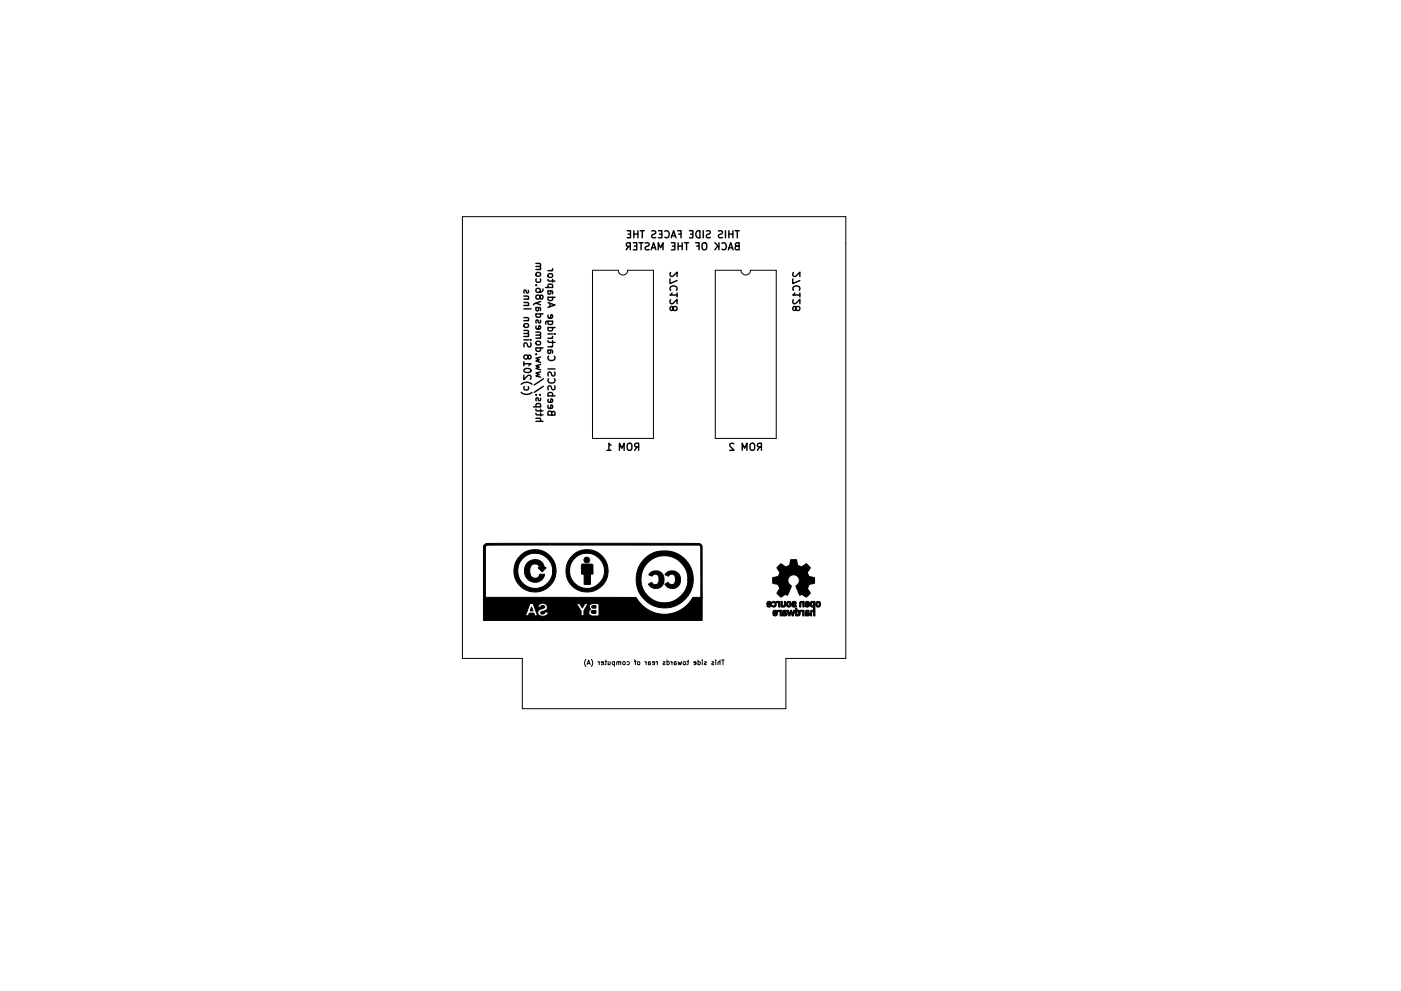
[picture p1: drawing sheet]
<svg xmlns="http://www.w3.org/2000/svg" width="297mm" height="210mm" viewBox="0 0 297 210" stroke-linecap="round" stroke-linejoin="round" font-family="sans-serif">
<g fill="none" stroke="#000" stroke-width=".3">
<path d="M113.6 56.5l.9 .1 .1 .4-.1 .2M113.6 55.9l.9 .1 .1 .3-.2 .2M113.6 57.2h1M113.7 59.2l-.1 .4 .3 .3 .6-.2v-.5M113.7 58l.6-.2 .2 .2 .1 .3-.3 .3h-.4l-.3-.3zM116.2 59.3l.2 .3h1.3M116.2 57.4h1M116.3 58.1h.7l.2 .3-.1 .3-.2 .2-.6-.1-.1-.2zM117.2 57l-.3 .4M117.2 59.3v.6M133 49h.7v1.5h-.7M133.2 49.7h.5"/>
<path d="M133.3 52.3l-.5 .7M133.6 52.3l-.7-.1-.1-.2 .1-.4 .7-.1v1.5M134.3 51.5h.7v1.5h-.7M134.4 49.7h.8M134.4 49v1.5M134.5 52.2h.5M135.2 49v1.5M135.5 51.5h.9M135.7 49h.9M135.9 51.5v1.5M136.2 49v1.5M136.8 51.6l.6-.1 .2 .3-.1 .3-.6 .3v.5l.2 .1 .5-.1"/>
<path d="M138.1 53l.5-1.5 .5 1.5M138.2 49h.5l.3 .1v.4l-.7 .3-.1 .4 .3 .3 .5-.1M138.2 52.6h.7M139.6 53v-1.5l.5 1.1 .5-1.1v1.5M139.6 49h.7v1.5h-.7M139.8 49.7h.5M141 49.1a.71 .71 0 0 1 .9 .5 .71 .71 0 0 1-.7 .9l-.2-.2M142.1 59.2v1l1.5-.7M142.2 57.8l-.1 .6 .4 .3 1.1-1v1M142.3 50.5l.5-1.5 .5 1.5M142.4 51.5h.7v1.5h-.7M142.5 50h.7"/>
<path d="M142.6 52.2h.5M143.7 49h.7v1.5M143.8 52.2h.8M143.8 51.5v1.5M143.9 49.7h.5M144.6 51.5v1.5M145.1 51.5h.9M145.6 51.5v1.5M146.2 49h.7v1.5h-.7M146.4 49.7h.5M147.5 51.5h.7v1.5M147.7 49.2l.7-.2v1.5a.78 .78 0 0 1-.8-.4 .78 .78 0 0 1 .1-.9z"/>
<path d="M147.7 52.2h.5M148.9 51.7l.3-.2a.5 .5 0 0 1 .7 .5v.5a.5 .5 0 0 1-.5 .5 .5 .5 0 0 1-.5-.5zM149.1 49v1.5M149.7 49h.6l.2 .1v.4l-.6 .3-.2 .4 .3 .3 .6-.1M151.6 51.5l.8 .9M152.2 52.1l-.6 .9M152.3 49h.6l.2 .1v.4l-.6 .3-.2 .4 .3 .3 .6-.1M152.4 51.5v1.5M153.1 51.6a.71 .71 0 0 1 1 .5 .71 .71 0 0 1-.7 .9l-.3-.1M153.8 49v1.5M154.4 53l.5-1.5 .5 1.5M154.5 49.7h.9"/>
<path d="M154.5 49v1.5M154.6 52.6h.7M155.4 49v1.5M155.9 49h.8M156.2 52.2l-.3 .3v.4l.2 .1h.6v-1.5l-.7 .1-.1 .3 .2 .2 .6 .1M156.3 49v1.5M168.1 59.2v1l1.5-.7M168.2 57.8l-.1 .6 .4 .3 1.1-1v1M111.1 79.6v.9l1-.9 .5 .3-.2 .6M111.1 77.2h1.5l-.5 .4M111.1 70.7l.9 .1 .1 .4-.2 .2M111.1 70.1l.9 .1 .1 .3-.2 .2"/>
<path d="M111.1 67.4l.9 .1 .1 .3-.2 .2M111.1 64.2h.9l.1 .4-.2 .2M111.1 62.8l.9 .1 .1 .3-.2 .3M111.1 76.7v.9M111.1 72.1h1M111.1 71.4h1M111.1 68h1M111.1 65.5h1.5M111.1 64.8h1M111.1 63.5h1M111.1 78.4a.89 .89 0 0 1 1.5 .3 .85 .85 0 0 1-1.5-.2zM111.1 68.8l.7-.1 .2 .1 .1 .4-.3 .3h-.4l-.3-.3z"/>
<path d="M111.9 75.6l-.3-.3h-.2l-.3 .3v.4l.5 .2 .3-.2 .2-.6 .4 .1 .1 .4-.2 .2-.2 .1-.3-.3M112 61.6l.1 .4-.2 .2-.3-.1-.1-.5h-.4v.6M112.4 72.1h.2M112.5 72.7l.1 .6-.2 .2h-.4l-.3-.6-.3-.2-.3 .3v.6M113.6 75.2h.2M113.6 71.1l.9 .1 .1 .3-.1 .2M113.6 70.5h.9l.1 .4-.2 .2M113.6 65.2l.9 .1v.6M113.6 60.5h.2M113.6 71.7h1M113.6 73.8h1.5M113.6 66.6h1.5"/>
<path d="M113.6 64.3l1 .4M113.7 73.8l-.1 .4 .3 .3 .6-.1v-.6M113.7 72.5l.6-.1 .2 .1 .1 .4-.3 .3h-.4l-.3-.3zM113.7 69.2l-.1 .4 .2 .2 .7-.1v-.5l-.2-.1-.2 .7M113.7 66.6l-.1 .4 .3 .3 .6-.1v-.6M113.7 65.2l-.1 .5 .2 .3 .3-.1 .2-.7M114.5 62.9l-.3-.3h-.3l-.3 .3 .2 .5 .4 .1 .2-.2 .2-.6h.5v.5l-.1 .2-.2 .1-.3-.3M114.5 68l.1 .3-.2 .2h-.2l-.1-.5h-.4v.5M114.6 78.9l-1 .3 .7 .3-.7 .2 1 .3M114.6 77.3l-1 .3 .7 .3-.7 .3 1 .3M114.6 75.7l-1 .3 .7 .3-.7 .3 1 .3M114.6 64l-1.3 .5-.2 .2"/>
<path d="M115.1 61.3v.4a1.01 1.01 0 0 1-1.5 0l.2-.5h.5l.2 .3v.4l-.2 .1M115.7 61h1.5M116.2 74.3l.9 .1v.5M116.2 72.3l.2 .3h1.3M116.2 64.2l1.5 .5-1.5 .5M116.2 61.7l.9 .1v.6M116.2 78.3h1.5M116.2 73.6h1M116.2 71.8h1M116.2 70.9h1M116.2 69.5h1.5M116.2 63.1h1.5"/>
<path d="M116.2 74.3v.5l.2 .2 .3-.1 .1-.6M116.2 69.5v.4l.3 .3 .6-.1v-.6M116.2 68.1v.5l.3 .3 .6-.2v-.6M116.2 66.9v.4l.2 .2 .7-.1v-.5l-.3-.1-.1 .7M116.2 63.1v.4l.3 .3 .6-.2v-.5M116.2 61.7v.5l.2 .2h.3l.1-.7M116.2 61v-.4l.3-.3 .6 .1v.6M116.3 75.6a.71 .71 0 0 0 .5 1 .71 .71 0 0 0 .9-.7l-.2-.3M116.6 64.4v.7M117.2 73.1l-.3 .5M117.2 71.4l-.3 .4M117.2 68.1h-1.2l-.3 .3v.4"/>
<path d="M117.2 72.3v.6M117.5 70.9h.2M117.6 78.9l.1 .6-.2 .2h-.4l-.3-.6-.3-.2-.3 .3v.6M142.2 61.6a.71 .71 0 0 1 .5-1 .71 .71 0 0 1 .9 .7l-.2 .3M142.2 63.6l-.1 .6 .4 .3 1.1-1v1M142.5 62.2l-.4 .4h1.5M142.7 65.3l-.3-.3-.2 .1-.1 .2v.4l.5 .1 .2-.6 .2-.2h.3l.3 .3v.3l-.3 .3h-.3l-.3-.3M143.6 62.2v.8M168.2 61.6a.71 .71 0 0 1 .5-1 .71 .71 0 0 1 .9 .7l-.2 .3M168.2 63.6l-.1 .6 .4 .3 1.1-1v1M168.5 62.2l-.4 .4h1.5M168.7 65.3l-.3-.3-.2 .1-.1 .2 .1 .4 .4 .1 .2-.6 .2-.2h.3l.3 .3v.3l-.3 .3h-.3l-.3-.3"/>
<path d="M169.6 62.2v.8M110.5 83.2a1.72 1.72 0 0 0 2.3 0M110.5 81.5a1.72 1.72 0 0 1 2.3 0M111.1 82v.5l.3 .2 .6-.1v-.6M113.1 86.3h1.5M113.6 88.7l.9 .1 .1 .4-.1 .2M113.6 87.7l.2 .3h1.3M113.6 86.8l.2 .4h1.3M113.6 83.7h.2M113.6 89.4h1.5M113.7 86.3l-.1-.4 .3-.3 .6 .1v.6M114.4 83.7h.1"/>
<path d="M114.5 84.5l.1 .3-.2 .2h-.2l-.1-.5h-.4v.5M114.6 86.8v.6M114.6 87.7v.5M115.2 82l-1.9 1.2M115.2 80.4l-1.9 1.3M116.2 84h1.5M116.2 86v.4l.2 .2h.7v-.6l-.3-.1-.1 .7M116.2 84.7v.4l.2 .3 .7-.1v-.6l-.3-.1-.1 .8M116.2 84v-.4l.3-.3 .6 .1v.6M116.3 80.4a.71 .71 0 0 0 .5 .9 .71 .71 0 0 0 .9-.7l-.2-.2M117 87.6l-.3-.4-.4 .1-.1 .2v.6h1.5l-.2-.7-.3-.1-.2 .1v.7M117.6 81.9l.1 .5-.2 .2h-.4l-.3-.6-.3-.1-.3 .2v.6"/>
<path d="M128.7 95.5h.8M129.5 94.5l-.4-.5v1.5M131.3 95.5v-1.5l.5 1.1 .5-1.1v1.5M133.2 94.1l.1-.1a.5 .5 0 0 1 .7 .5v.5a.5 .5 0 0 1-.5 .6 .5 .5 0 0 1-.5-.6v-.5zM135 94.8l-.5 .7M135.4 94.8h-.7l-.2-.3 .1-.3 .8-.2v1.5M155.6 94.2l-.6-.2-.3 .5 1 1h-1M157.4 95.5v-1.5l.5 1.1 .5-1.1v1.5M159.2 94.1l.2-.1a.5 .5 0 0 1 .6 .5v.5a.5 .5 0 0 1-.5 .6 .5 .5 0 0 1-.5-.6v-.5zM161.1 94.8l-.5 .7M161.4 94.8h-.7l-.1-.3 .1-.3 .7-.2v1.5"/>
</g>
<g fill="none" stroke="#000" stroke-width=".21">
<path d="M98 46h81.3v93.7h-12.7v10.7h-55.9v-10.7h-12.7zM125.6 57.3h5.5a1 1 0 0 0 1 1 1 1 0 0 0 1-1h5.4v35.7h-12.9zM151.7 57.3h5.4a1 1 0 0 0 1 1 1 1 0 0 0 1-1h5.5v35.7h-12.9zM124.2 139.9a1.15 1.15 0 0 0 0 1.5M125.4 139.9a1.15 1.15 0 0 1 0 1.5M124.5 141l.3-1 .3 1M124.6 140.7h.4M126.8 140.4l.2 .2M127 140.4v.6M127.9 140.7l-.4-.1v-.2h.3l.1 .1v.5h-.4M128.2 140.4h.4M128.5 140v.9l-.3 .1"/>
<path d="M128.9 140.4v.6M129.4 140.4l-.1 .6-.4-.1M130.3 140.4h-.3l-.2 .2 .1 .4h.4M130.3 140.4v1M131.2 140.5l-.4-.1v.6M131.6 140.5l-.4-.1v.6M131.6 140.4v.6M132.1 140.5h.4v.5l-.4-.1zM132.9 140.4h.3l.2 .2-.1 .4h-.4M134.5 140l.2 .2v.8M134.5 140.4h.4M135.2 140.5h.4v.5l-.4-.1z"/>
<path d="M136.7 140.4l.3 .2M137 140.4v.6M137.5 140.6l.4 .2-.1 .2h-.3M137.9 140.4h-.4v.6M138.8 140.7l-.5-.1 .1-.2h.3l.1 .1v.5h-.4M139.1 140.4l.3 .2M139.4 140.4v.6M140.6 140.4l.4 .1-.4 .2v.3h.4M141.4 140.4h.3l.2 .2-.1 .4h-.4M141.4 140v1M142.2 140.4l.3 .2M142.5 140.4v.6"/>
<path d="M142.9 140.6l.5 .2-.1 .2h-.4M143.4 140.4h-.4l-.1 .6M143.8 140.4l.1 .6 .2-.4 .2 .4 .2-.6M144.9 140.5h.4v.5l-.4-.1zM145.7 140.4h.3M145.9 140v.9l-.2 .1M147.6 140.7l-.5-.1v-.2h.3l.2 .1-.1 .5h-.4M148 140.4h.3l.2 .2-.1 .4h-.4M148 140v1M148.9 140v.1M148.9 140.4v.6M149.4 140.4l.4 .1-.4 .2v.3h.4"/>
<path d="M150.9 140.4l.4 .1-.4 .2v.3h.4M151.8 140v.1M151.8 140.4v.6M152.7 140.5l-.4-.1-.1 .6M152.7 140v1M153 140h.6M153.3 140v1"/>
</g>
<g fill="#000" stroke="#000" stroke-width=".21">
<path d="M110.4 117.8a4.4 4.4 0 0 1 4.9-.8 4.4 4.4 0 0 1 2.6 4.2h-.7a3.7 3.7 0 0 0-5.2-3.5 3.7 3.7 0 0 0-1.1 6.2 3.7 3.7 0 0 0 6.1-1.5l.2-1.2h.7a4.5 4.5 0 0 1-6.3 4 4.5 4.5 0 0 1-1.2-7.4zM111.9 119.3a2.07 2.07 0 0 1 2.1-.5 2.07 2.07 0 0 1 1.4 1.7h.4l-.8 .8-.9-.8h.2a.98 .98 0 0 0-1.1-.9 .98 .98 0 0 0-.8 1 1.43 1.43 0 0 0 1.1 2.1l.7-.3 .2-.6h1.1a2.21 2.21 0 0 1-2.8 1.6 2.21 2.21 0 0 1-1.5-2.8l.2-.6zM123.5 119.7h1.3a.63 .63 0 0 1 .8 .1 .63 .63 0 0 1 .1 .7v1.3h-.5v2.2h-1.4v-2.2h-.5v-1.9zM121.5 117.8a4.4 4.4 0 0 1 4.8-.8 4.4 4.4 0 0 1 2.6 4.2h-.7a3.7 3.7 0 0 0-5.5-3.3 3.7 3.7 0 0 0-.4 6.4 3.7 3.7 0 0 0 5.8-2.7l.1-.4h.7a4.5 4.5 0 0 1-6.3 4 4.5 4.5 0 0 1-1.1-7.4zM102.6 115.7a1.94 1.94 0 0 1 1.9-.4h43.8l.6 .6v10.8h-.3v-10.8l-.3-.2h-44.4a.72 .72 0 0 0-.8 .1 .72 .72 0 0 0-.2 .8v10.1l31.4 .1a.62 .62 0 0 1 .9 .5l.6 .8h-11.8l-.5 .9-.6-.9h-.6l.9 1.7h-7.6a.49 .49 0 0 1-.4 .5 .49 .49 0 0 1-.6-.4l.6-.2a.89 .89 0 0 0 .8-1.2 .89 .89 0 0 0-1.3-.5l-.4 .3-.3 .5h.5a.51 .51 0 0 1 .5-.3 .51 .51 0 0 1 .5 .3l-.8 .4a.73 .73 0 0 0-.7 .6 .73 .73 0 0 0 .4 .8h-.4l-1-2.5-.6-.1-1 2.6h.6l.2-.5h1l.2 .6 1-.1a1.24 1.24 0 0 0 1.9-.8h6.9v.9h.6v-1.1l.9-1.5h.8a.64 .64 0 0 0-.6 .5 .64 .64 0 0 0 .3 .7 .76 .76 0 0 0-.4 .8 .76 .76 0 0 0 .7 .6h1.5v-2.6h8.8l.3 .3a6.8 6.8 0 0 0 10.8-1.7h2l-.1 4.9h-46.3v-15.7zM136.9 118.3a6.1 6.1 0 0 1 6.5-.9 6.1 6.1 0 0 1 3.6 5.5h-1.2a5 5 0 0 0-6.8-4.6 5 5 0 0 0-1.8 8.1 5 5 0 0 0 8.2-1.3l.3-1 .1-1.2h1.2a6.1 6.1 0 0 1-8.6 5.5 6.1 6.1 0 0 1-1.5-10.1zM165.2 119.9l.1-.1a.32 .32 0 0 1 .3-.2 .32 .32 0 0 1 .3 .2l.7 .5 .8-.4 .2-1.2h1.3l.2 1.2 .8 .4 .8-.5a.32 .32 0 0 1 .3-.2 .32 .32 0 0 1 .3 .3l.2 .2a.38 .38 0 0 1 .3 .3 .38 .38 0 0 1-.2 .4 .87 .87 0 0 0-.3 .9 .87 .87 0 0 0 .6 .7h.3a.45 .45 0 0 1 .5 .2 .45 .45 0 0 1 0 .5v.2a.39 .39 0 0 1 0 .4 .39 .39 0 0 1-.4 .2 .95 .95 0 0 0-1 .6 .95 .95 0 0 0 .3 1 .34 .34 0 0 1 .2 .4 .34 .34 0 0 1-.3 .3l-.2 .2a.42 .42 0 0 1-.4 .3 .42 .42 0 0 1-.4-.3 .77 .77 0 0 0-.9-.1l-.9-1.9a1.25 1.25 0 0 0 .6-2 1.25 1.25 0 0 0-2 0 1.25 1.25 0 0 0 .5 1.9l-.8 2a.74 .74 0 0 0-1.1 .2l-.1 .1a.3 .3 0 0 1-.3 .1 .3 .3 0 0 1-.2-.3l-.3-.2a.45 .45 0 0 1-.3-.4 .45 .45 0 0 1 .3-.5 .93 .93 0 0 0 .1-1 .93 .93 0 0 0-.9-.5 .39 .39 0 0 1-.4-.2 .39 .39 0 0 1 0-.4v-.2a.39 .39 0 0 1 0-.4 .39 .39 0 0 1 .5-.1 .87 .87 0 0 0 .8-.4 .87 .87 0 0 0 0-1l-.1-.2a.45 .45 0 0 1-.3-.5 .45 .45 0 0 1 .4-.4zM112.7 128.8l.3 .8h-.6zM125.5 128.6l.8-.1v.5h-.3a.33 .33 0 0 1-.4 0 .33 .33 0 0 1-.1-.4zM125.4 129.6l.9-.1v.7h-.4a.39 .39 0 0 1-.4-.1 .39 .39 0 0 1-.1-.5zM137.9 121.5a1.85 1.85 0 0 1 2.4 .1 1.85 1.85 0 0 1 .3 2.3 1.74 1.74 0 0 1-1.5 1 1.74 1.74 0 0 1-1.6-1l.7-.4a.85 .85 0 0 0 1.1 .5 .85 .85 0 0 0 .4-1.1 .85 .85 0 0 0-.5-1 .85 .85 0 0 0-1 .3l-.6-.3zM141.3 121.5a1.84 1.84 0 0 1 3 1.3 1.84 1.84 0 0 1-2.7 1.8l-.6-.7 .6-.4a.85 .85 0 0 0 1.1 .5 .85 .85 0 0 0 .5-1.1 .85 .85 0 0 0-.5-1 .85 .85 0 0 0-1.1 .3l-.6-.3z"/>
<path d="M162.7 127.8a.49 .49 0 0 1 .5-.2 .49 .49 0 0 1 .3 .4h-.2a.21 .21 0 0 0-.2-.2 .21 .21 0 0 0-.2 .3h.7a.56 .56 0 0 1-.3 .7 .56 .56 0 0 1-.7-.2l.2-.1a.29 .29 0 0 0 .3 .1 .29 .29 0 0 0 .2-.3h-.7zM163.6 127.8a.59 .59 0 0 1 .8 0 .59 .59 0 0 1 0 .8 .59 .59 0 0 1-.8 0l.1-.1a.34 .34 0 0 0 .5 0 .34 .34 0 0 0 .1-.4 .34 .34 0 0 0-.5-.1zM164 129.6a.49 .49 0 0 1 .5-.1 .49 .49 0 0 1 .3 .4h-.2a.21 .21 0 0 0-.2-.2 .21 .21 0 0 0-.2 .3l.6-.1a.5 .5 0 0 1-.2 .7 .5 .5 0 0 1-.7-.2h.5l.2-.2h-.8zM164.6 127.7l.8-.1v1.2h-.3v-.8l-.4-.1zM164.8 129.6l.9-.1v1.2h-.3v-.4a.36 .36 0 0 0 0-.5 .36 .36 0 0 0-.4-.1zM166 129.6l.3-.1 .5 .1-.2 .2a.24 .24 0 0 0-.3-.1 .24 .24 0 0 0-.1 .3h.5l.2 .3-.7-.1a.25 .25 0 0 0 .1 .2 .25 .25 0 0 0 .3-.1h.3a.72 .72 0 0 1-.9 .4h-.1zM165.6 127.6h.3v.4a.33 .33 0 0 0-.1 .4 .33 .33 0 0 0 .4 .1l.1-.9h.3v.6a.46 .46 0 0 1-.2 .5 .46 .46 0 0 1-.5 0l-.3 .1zM166.9 127.7a.51 .51 0 0 1 .6 0 .51 .51 0 0 1 .2 .5l-.2-.1a.25 .25 0 0 0-.3-.3 .25 .25 0 0 0-.2 .4 .24 .24 0 0 0 .2 .3 .24 .24 0 0 0 .3-.2v-.1h.2a.54 .54 0 0 1-.6 .6 .54 .54 0 0 1-.3-.8zM166.9 129.5h.2l.3 .7 .2-.7h.2l.3 .7 .2-.7h.3l-.4 1.2h-.2l-.3-.8-.2 .8h-.3zM167.9 127.7h.1a.44 .44 0 0 1 .8 .2 .44 .44 0 0 1-.6 .5h-.1a.33 .33 0 0 0 .6 0 .28 .28 0 0 1 0 .4 .28 .28 0 0 1-.4 0 .42 .42 0 0 1-.4-.5 .42 .42 0 0 1 .6-.3l-.1-.2-.4 .1zM168.7 129h.2v.6l.1-.1a.45 .45 0 0 1 .5 .1 .45 .45 0 0 1 .1 .5h-.2a.26 .26 0 0 0-.3-.4 .27 .27 0 0 0-.2 .5 .23 .23 0 0 0 .3 .2 .23 .23 0 0 0 .2-.3l.2 .1a.44 .44 0 0 1-.2 .4 .44 .44 0 0 1-.5 0l-.2 .1zM169.6 127.7l.9-.1v1.2h-.3v-.6a.25 .25 0 0 0-.2-.4 .25 .25 0 0 0-.2 .4v.6h-.3z"/>
<path d="M169.6 129.5h.8v1.2h-.2l-.1-.9-.3-.1zM170.9 127.7a.49 .49 0 0 1 .5-.1 .49 .49 0 0 1 .3 .4h-.3a.21 .21 0 0 0-.2-.2 .21 .21 0 0 0-.2 .3l.7-.1a.54 .54 0 0 1-.3 .7 .54 .54 0 0 1-.7-.1l.2-.1 .3 .1 .2-.3h-.7zM170.8 129.6l.5-.1 .3 .1-.3 .1a.22 .22 0 0 0-.3 0 .22 .22 0 0 0 0 .3h.5l.2 .3-.7-.1a.23 .23 0 0 0 .1 .2 .23 .23 0 0 0 .3-.1h.3a.81 .81 0 0 1-1 .4zM171.9 127.7l.9-.1v.6h-.3v-.2a.3 .3 0 0 0-.5 .1 .3 .3 0 0 0 .2 .4h.2l.1-.3h.3v2.5h-.3v-.5a.27 .27 0 0 0 0-.4 .27 .27 0 0 0-.4 0v.9h-.3v-1l.3-.2h.4v-.8a.51 .51 0 0 1-.6-.1 .51 .51 0 0 1-.1-.6zM173.1 127.8a.5 .5 0 0 1 .6-.2 .5 .5 0 0 1 .3 .6h-.3a.29 .29 0 0 0-.4-.2 .29 .29 0 0 0 0 .5 .25 .25 0 0 0 .3 0 .25 .25 0 0 0 .1-.3h.3a.53 .53 0 0 1-.6 .6 .53 .53 0 0 1-.4-.7z"/>
<circle cx="124.4" cy="118.8" r=".62"/>
</g>
</svg>
